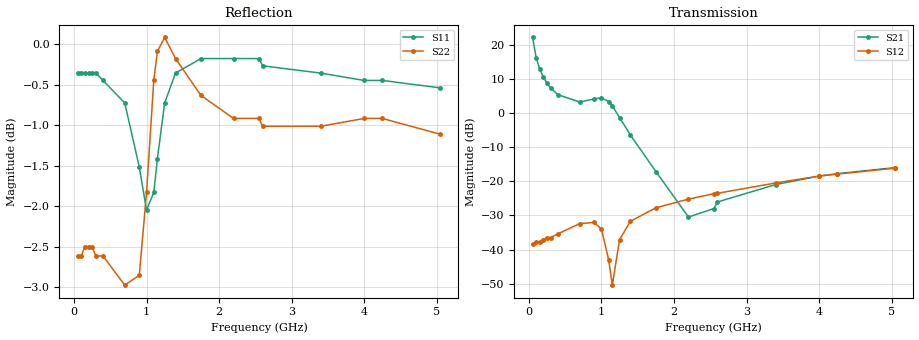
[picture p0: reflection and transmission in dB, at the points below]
!AT-36408
!S-PARAMETERS at Vce=3.6 V  Ic=200 mA.  LAST UPDATED 08-05-96
# ghz s ma r 50
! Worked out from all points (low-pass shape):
!   101 points, 50 MHz to 5.05 GHz, reference 50 ohm
!   highest |S21| = 22.33 dB at 50 MHz (marker M1); lowest = -30.5 dB at 2.2 GHz (marker M2)
!   |S21| within 3 dB of the highest: start of sweep to 75.3 MHz
!   lowest |S11| = -2.0 dB at 1 GHz (marker M3), VSWR 8.52, Z = 5.91 + j4.31 ohm
!   |S11| at or under -10 dB: nowhere
!   |S22| runs from -3.1 to 0.1 dB; largest |S21 - S12| = 13
!   S11 on the Smith chart (normalised r, x): 50 MHz: 0.02, -0.04; 900 MHz: 0.09, +0.10; 1.4 GHz: 0.02, +0.07; 2.6 GHz: 0.02, +0.24; 4 GHz: 0.03, +0.43; 5.05 GHz: 0.04, +0.66
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0.05  0.96 -175.0  13.08 93.0  0.012 11.0  0.74 -169.0
0.1  0.96 -178.0  6.61 88.0  0.013 13.0  0.74 -174.0
0.15  0.96 180.0  4.45 85.0  0.013 17.0  0.75 -176.0
0.2  0.96 179.0  3.39 82.0  0.014 21.0  0.75 -177.0
0.25  0.96 177.0  2.76 80.0  0.015 24.0  0.75 -177.0
0.3  0.96 177.0  2.36 77.0  0.015 27.0  0.74 -177.0
0.4  0.95 175.0  1.88 72.0  0.017 31.0  0.74 -177.0
0.7  0.92 170.0  1.47 51.0  0.024 29.0  0.71 -174.0
0.9  0.84 168.0  1.63 24.0  0.025 10.0  0.72 -165.0
1  0.79 170.0  1.7 0.0  0.02 -14.0  0.81 -160.0
1.1  0.81 176.0  1.49 -31.0  0.007 -57.0  0.95 -163.0
1.15  0.85 177.0  1.29 -45.0  0.003 -155.0  0.99 -166.0
1.25  0.92 175.0  0.87 -68.0  0.014 126.0  1.01 -172.0
1.4  0.96 172.0  0.48 -89.0  0.026 104.0  0.98 -176.0
1.75  0.98 165.0  0.14 -116.0  0.041 88.0  0.93 -179.0
2.2  0.98 159.0  0.03 176.0  0.055 81.0  0.9 -180.0
2.55  0.98 154.0  0.04 105.0  0.066 77.0  0.9 180.0
2.6  0.97 153.0  0.05 100.0  0.067 76.0  0.89 180.0
3.4  0.96 142.0  0.09 73.0  0.095 70.0  0.89 178.0
4  0.95 133.0  0.12 63.0  0.12 62.0  0.9 175.0
4.25  0.95 129.0  0.13 59.0  0.128 58.0  0.9 174.0
5.05  0.94 113.0  0.16 47.0  0.157 48.0  0.88 167.0
